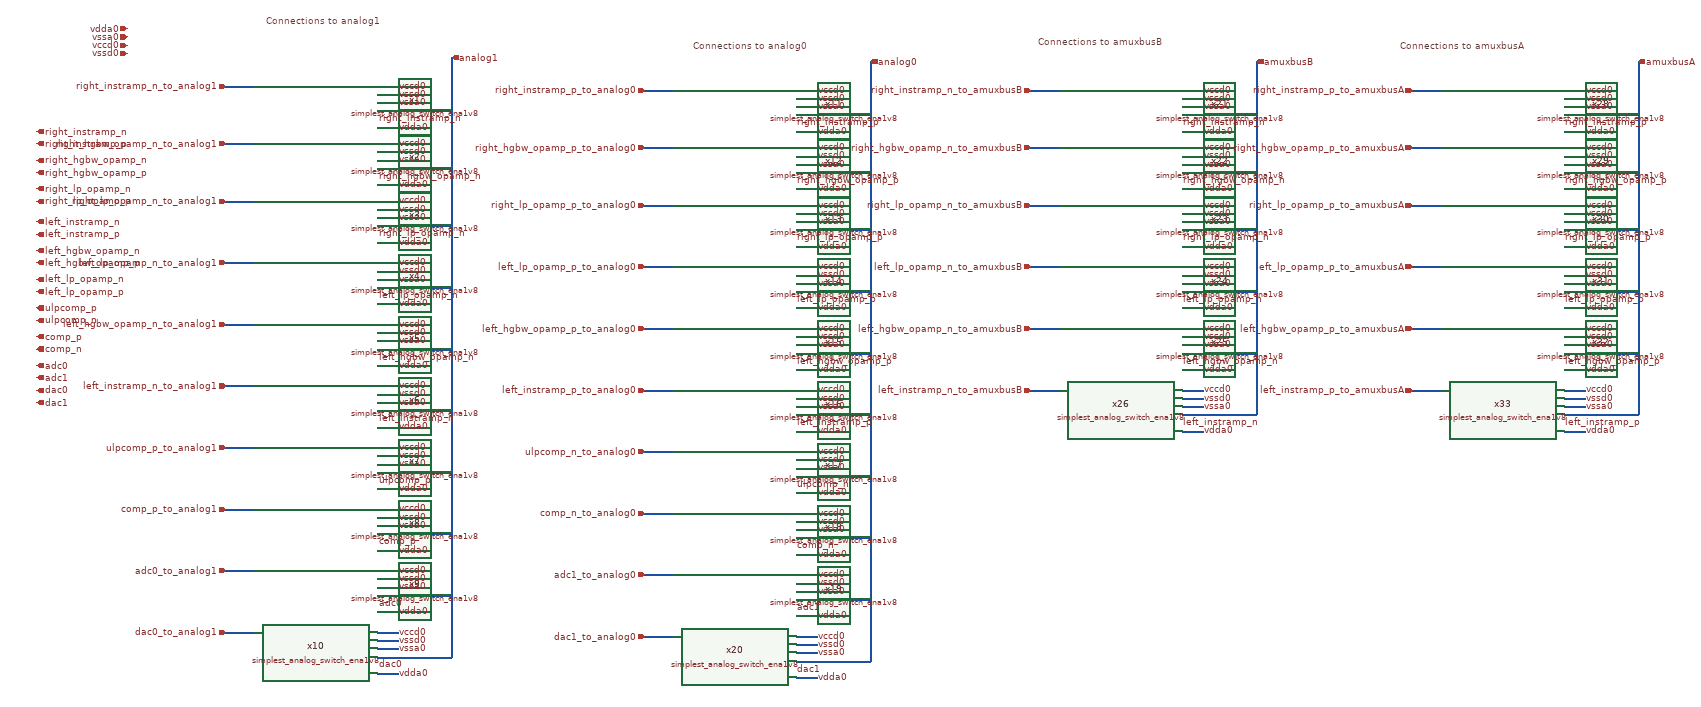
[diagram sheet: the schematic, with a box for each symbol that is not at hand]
v {xschem version=3.4.5 file_version=1.2
}
G {}
K {}
V {}
S {}
E {}
T {Connections to analog1} -110 -190 0 0 0.4 0.4 {}
T {Connections to analog0} 930 -130 0 0 0.4 0.4 {}
T {Connections to amuxbusA} 2650 -130 0 0 0.4 0.4 {}
T {Connections to amuxbusB} 1770 -140 0 0 0.4 0.4 {}
N -210 -20 -140 -20 {
lab=right_instramp_n_to_analog1}
N 160 -20 210 -20 {
lab=vccd0}
N 160 0 210 0 {
lab=vssd0}
N 160 20 210 20 {
lab=vssa0}
N 160 80 210 80 {
lab=vdda0}
N -210 120 -140 120 {
lab=right_hgbw_opamp_n_to_analog1}
N 160 120 210 120 {
lab=vccd0}
N 160 140 210 140 {
lab=vssd0}
N 160 160 210 160 {
lab=vssa0}
N 160 220 210 220 {
lab=vdda0}
N -210 260 -140 260 {
lab=right_lp_opamp_n_to_analog1}
N 160 260 210 260 {
lab=vccd0}
N 160 280 210 280 {
lab=vssd0}
N 160 300 210 300 {
lab=vssa0}
N 160 360 210 360 {
lab=vdda0}
N -210 410 -140 410 {
lab=left_lp_opamp_n_to_analog1}
N 160 410 210 410 {
lab=vccd0}
N 160 430 210 430 {
lab=vssd0}
N 160 450 210 450 {
lab=vssa0}
N 160 510 210 510 {
lab=vdda0}
N 160 40 340 40 {
lab=analog1}
N 160 180 340 180 {
lab=analog1}
N 160 320 340 320 {
lab=analog1}
N 160 470 340 470 {
lab=analog1}
N -210 560 -140 560 {
lab=left_hgbw_opamp_n_to_analog1}
N 160 560 210 560 {
lab=vccd0}
N 160 580 210 580 {
lab=vssd0}
N 160 600 210 600 {
lab=vssa0}
N 160 660 210 660 {
lab=vdda0}
N 160 620 340 620 {
lab=analog1}
N -210 710 -140 710 {
lab=left_instramp_n_to_analog1}
N 160 710 210 710 {
lab=vccd0}
N 160 730 210 730 {
lab=vssd0}
N 160 750 210 750 {
lab=vssa0}
N 160 810 210 810 {
lab=vdda0}
N 160 770 340 770 {
lab=analog1}
N -210 860 -140 860 {
lab=ulpcomp_p_to_analog1}
N 160 860 210 860 {
lab=vccd0}
N 160 880 210 880 {
lab=vssd0}
N 160 900 210 900 {
lab=vssa0}
N 160 960 210 960 {
lab=vdda0}
N 160 920 340 920 {
lab=analog1}
N -210 1010 -140 1010 {
lab=comp_p_to_analog1}
N 160 1010 210 1010 {
lab=vccd0}
N 160 1030 210 1030 {
lab=vssd0}
N 160 1050 210 1050 {
lab=vssa0}
N 160 1110 210 1110 {
lab=vdda0}
N 160 1070 340 1070 {
lab=analog1}
N -210 1160 -140 1160 {
lab=adc0_to_analog1}
N 160 1160 210 1160 {
lab=vccd0}
N 160 1180 210 1180 {
lab=vssd0}
N 160 1200 210 1200 {
lab=vssa0}
N 160 1260 210 1260 {
lab=vdda0}
N 160 1220 340 1220 {
lab=analog1}
N -210 1310 -140 1310 {
lab=dac0_to_analog1}
N 160 1310 210 1310 {
lab=vccd0}
N 160 1330 210 1330 {
lab=vssd0}
N 160 1350 210 1350 {
lab=vssa0}
N 160 1410 210 1410 {
lab=vdda0}
N 160 1370 340 1370 {
lab=analog1}
N 340 -90 340 1370 {
lab=analog1}
N 810 -10 880 -10 {
lab=right_instramp_p_to_analog0}
N 1180 -10 1230 -10 {
lab=vccd0}
N 1180 10 1230 10 {
lab=vssd0}
N 1180 30 1230 30 {
lab=vssa0}
N 1180 90 1230 90 {
lab=vdda0}
N 810 130 880 130 {
lab=right_hgbw_opamp_p_to_analog0}
N 1180 130 1230 130 {
lab=vccd0}
N 1180 150 1230 150 {
lab=vssd0}
N 1180 170 1230 170 {
lab=vssa0}
N 1180 230 1230 230 {
lab=vdda0}
N 810 270 880 270 {
lab=right_lp_opamp_p_to_analog0}
N 1180 270 1230 270 {
lab=vccd0}
N 1180 290 1230 290 {
lab=vssd0}
N 1180 310 1230 310 {
lab=vssa0}
N 1180 370 1230 370 {
lab=vdda0}
N 810 420 880 420 {
lab=left_lp_opamp_p_to_analog0}
N 1180 420 1230 420 {
lab=vccd0}
N 1180 440 1230 440 {
lab=vssd0}
N 1180 460 1230 460 {
lab=vssa0}
N 1180 520 1230 520 {
lab=vdda0}
N 1180 50 1360 50 {
lab=analog0}
N 1180 190 1360 190 {
lab=analog0}
N 1180 330 1360 330 {
lab=analog0}
N 1180 480 1360 480 {
lab=analog0}
N 810 570 880 570 {
lab=left_hgbw_opamp_p_to_analog0}
N 1180 570 1230 570 {
lab=vccd0}
N 1180 590 1230 590 {
lab=vssd0}
N 1180 610 1230 610 {
lab=vssa0}
N 1180 670 1230 670 {
lab=vdda0}
N 1180 630 1360 630 {
lab=analog0}
N 810 720 880 720 {
lab=left_instramp_p_to_analog0}
N 1180 720 1230 720 {
lab=vccd0}
N 1180 740 1230 740 {
lab=vssd0}
N 1180 760 1230 760 {
lab=vssa0}
N 1180 820 1230 820 {
lab=vdda0}
N 1180 780 1360 780 {
lab=analog0}
N 810 870 880 870 {
lab=ulpcomp_n_to_analog0}
N 1180 870 1230 870 {
lab=vccd0}
N 1180 890 1230 890 {
lab=vssd0}
N 1180 910 1230 910 {
lab=vssa0}
N 1180 970 1230 970 {
lab=vdda0}
N 1180 930 1360 930 {
lab=analog0}
N 810 1020 880 1020 {
lab=comp_n_to_analog0}
N 1180 1020 1230 1020 {
lab=vccd0}
N 1180 1040 1230 1040 {
lab=vssd0}
N 1180 1060 1230 1060 {
lab=vssa0}
N 1180 1120 1230 1120 {
lab=vdda0}
N 1180 1080 1360 1080 {
lab=analog0}
N 810 1170 880 1170 {
lab=adc1_to_analog0}
N 1180 1170 1230 1170 {
lab=vccd0}
N 1180 1190 1230 1190 {
lab=vssd0}
N 1180 1210 1230 1210 {
lab=vssa0}
N 1180 1270 1230 1270 {
lab=vdda0}
N 1180 1230 1360 1230 {
lab=analog0}
N 810 1320 880 1320 {
lab=dac1_to_analog0}
N 1180 1320 1230 1320 {
lab=vccd0}
N 1180 1340 1230 1340 {
lab=vssd0}
N 1180 1360 1230 1360 {
lab=vssa0}
N 1180 1420 1230 1420 {
lab=vdda0}
N 1180 1380 1360 1380 {
lab=analog0}
N 1360 -80 1360 1380 {
lab=analog0}
N 1750 -10 1820 -10 {
lab=right_instramp_n_to_amuxbusA}
N 2120 -10 2170 -10 {
lab=vccd0}
N 2120 10 2170 10 {
lab=vssd0}
N 2120 30 2170 30 {
lab=vssa0}
N 2120 90 2170 90 {
lab=vdda0}
N 1750 130 1820 130 {
lab=right_hgbw_opamp_n_to_amuxbusA}
N 2120 130 2170 130 {
lab=vccd0}
N 2120 150 2170 150 {
lab=vssd0}
N 2120 170 2170 170 {
lab=vssa0}
N 2120 230 2170 230 {
lab=vdda0}
N 1750 270 1820 270 {
lab=right_lp_opamp_n_to_amuxbusA}
N 2120 270 2170 270 {
lab=vccd0}
N 2120 290 2170 290 {
lab=vssd0}
N 2120 310 2170 310 {
lab=vssa0}
N 2120 370 2170 370 {
lab=vdda0}
N 1750 420 1820 420 {
lab=left_lp_opamp_n_to_amuxbusA}
N 2120 420 2170 420 {
lab=vccd0}
N 2120 440 2170 440 {
lab=vssd0}
N 2120 460 2170 460 {
lab=vssa0}
N 2120 520 2170 520 {
lab=vdda0}
N 2120 50 2300 50 {
lab=amuxbusA}
N 2120 190 2300 190 {
lab=amuxbusA}
N 2120 330 2300 330 {
lab=amuxbusA}
N 2120 480 2300 480 {
lab=amuxbusA}
N 1750 570 1820 570 {
lab=left_hgbw_opamp_n_to_amuxbusA}
N 2120 570 2170 570 {
lab=vccd0}
N 2120 590 2170 590 {
lab=vssd0}
N 2120 610 2170 610 {
lab=vssa0}
N 2120 670 2170 670 {
lab=vdda0}
N 2120 630 2300 630 {
lab=amuxbusA}
N 1750 720 1820 720 {
lab=left_instramp_n_to_amuxbusA}
N 2120 720 2170 720 {
lab=vccd0}
N 2120 740 2170 740 {
lab=vssd0}
N 2120 760 2170 760 {
lab=vssa0}
N 2120 820 2170 820 {
lab=vdda0}
N 2120 780 2300 780 {
lab=amuxbusA}
N 2680 -10 2750 -10 {
lab=right_instramp_p_to_amuxbusB}
N 3050 -10 3100 -10 {
lab=vccd0}
N 3050 10 3100 10 {
lab=vssd0}
N 3050 30 3100 30 {
lab=vssa0}
N 3050 90 3100 90 {
lab=vdda0}
N 2680 130 2750 130 {
lab=right_hgbw_opamp_p_to_amuxbusB}
N 3050 130 3100 130 {
lab=vccd0}
N 3050 150 3100 150 {
lab=vssd0}
N 3050 170 3100 170 {
lab=vssa0}
N 3050 230 3100 230 {
lab=vdda0}
N 2680 270 2750 270 {
lab=right_lp_opamp_p_to_amuxbusB}
N 3050 270 3100 270 {
lab=vccd0}
N 3050 290 3100 290 {
lab=vssd0}
N 3050 310 3100 310 {
lab=vssa0}
N 3050 370 3100 370 {
lab=vdda0}
N 2680 420 2750 420 {
lab=left_lp_opamp_p_to_amuxbusB}
N 3050 420 3100 420 {
lab=vccd0}
N 3050 440 3100 440 {
lab=vssd0}
N 3050 460 3100 460 {
lab=vssa0}
N 3050 520 3100 520 {
lab=vdda0}
N 3050 50 3230 50 {
lab=amuxbusB}
N 3050 190 3230 190 {
lab=amuxbusB}
N 3050 330 3230 330 {
lab=amuxbusB}
N 3050 480 3230 480 {
lab=amuxbusB}
N 2680 570 2750 570 {
lab=left_hgbw_opamp_p_to_amuxbusB}
N 3050 570 3100 570 {
lab=vccd0}
N 3050 590 3100 590 {
lab=vssd0}
N 3050 610 3100 610 {
lab=vssa0}
N 3050 670 3100 670 {
lab=vdda0}
N 3050 630 3230 630 {
lab=amuxbusB}
N 2680 720 2750 720 {
lab=left_instramp_p_to_amuxbusB}
N 3050 720 3100 720 {
lab=vccd0}
N 3050 740 3100 740 {
lab=vssd0}
N 3050 760 3100 760 {
lab=vssa0}
N 3050 820 3100 820 {
lab=vdda0}
N 3050 780 3230 780 {
lab=amuxbusB}
N 2300 -80 2300 780 {
lab=amuxbusA}
N 3230 -80 3230 780 {
lab=amuxbusB}
C {simplest_analog_switch_ena1v8.sym} 10 30 0 0 {name=x1}
C {devices/iopin.sym} -450 -120 0 0 {name=p1 lab=vccd0}
C {devices/ipin.sym} -210 -20 0 0 {name=p2 lab=right_instramp_n_to_analog1}
C {devices/iopin.sym} -450 -160 0 0 {name=p3 lab=vdda0}
C {devices/iopin.sym} -450 -140 0 0 {name=p4 lab=vssa0}
C {devices/iopin.sym} -450 -100 0 0 {name=p5 lab=vssd0}
C {devices/lab_pin.sym} 210 -20 0 1 {name=p6 sig_type=std_logic lab=vccd0}
C {devices/lab_pin.sym} 210 0 0 1 {name=p7 sig_type=std_logic lab=vssd0}
C {devices/lab_pin.sym} 210 20 0 1 {name=p8 sig_type=std_logic lab=vssa0}
C {devices/lab_pin.sym} 210 80 0 1 {name=p9 sig_type=std_logic lab=vdda0}
C {simplest_analog_switch_ena1v8.sym} 10 170 0 0 {name=x2}
C {devices/ipin.sym} -210 120 0 0 {name=p10 lab=right_hgbw_opamp_n_to_analog1}
C {devices/lab_pin.sym} 210 120 0 1 {name=p11 sig_type=std_logic lab=vccd0}
C {devices/lab_pin.sym} 210 140 0 1 {name=p12 sig_type=std_logic lab=vssd0}
C {devices/lab_pin.sym} 210 160 0 1 {name=p13 sig_type=std_logic lab=vssa0}
C {devices/lab_pin.sym} 210 220 0 1 {name=p14 sig_type=std_logic lab=vdda0}
C {simplest_analog_switch_ena1v8.sym} 10 310 0 0 {name=x3}
C {devices/ipin.sym} -210 260 0 0 {name=p15 lab=right_lp_opamp_n_to_analog1}
C {devices/lab_pin.sym} 210 260 0 1 {name=p16 sig_type=std_logic lab=vccd0}
C {devices/lab_pin.sym} 210 280 0 1 {name=p17 sig_type=std_logic lab=vssd0}
C {devices/lab_pin.sym} 210 300 0 1 {name=p18 sig_type=std_logic lab=vssa0}
C {devices/lab_pin.sym} 210 360 0 1 {name=p19 sig_type=std_logic lab=vdda0}
C {simplest_analog_switch_ena1v8.sym} 10 460 0 0 {name=x4}
C {devices/ipin.sym} -210 410 0 0 {name=p20 lab=left_lp_opamp_n_to_analog1}
C {devices/lab_pin.sym} 210 410 0 1 {name=p21 sig_type=std_logic lab=vccd0}
C {devices/lab_pin.sym} 210 430 0 1 {name=p22 sig_type=std_logic lab=vssd0}
C {devices/lab_pin.sym} 210 450 0 1 {name=p23 sig_type=std_logic lab=vssa0}
C {devices/lab_pin.sym} 210 510 0 1 {name=p24 sig_type=std_logic lab=vdda0}
C {simplest_analog_switch_ena1v8.sym} 10 610 0 0 {name=x5}
C {devices/ipin.sym} -210 560 0 0 {name=p25 lab=left_hgbw_opamp_n_to_analog1}
C {devices/lab_pin.sym} 210 560 0 1 {name=p26 sig_type=std_logic lab=vccd0}
C {devices/lab_pin.sym} 210 580 0 1 {name=p27 sig_type=std_logic lab=vssd0}
C {devices/lab_pin.sym} 210 600 0 1 {name=p28 sig_type=std_logic lab=vssa0}
C {devices/lab_pin.sym} 210 660 0 1 {name=p29 sig_type=std_logic lab=vdda0}
C {simplest_analog_switch_ena1v8.sym} 10 760 0 0 {name=x6}
C {devices/ipin.sym} -210 710 0 0 {name=p30 lab=left_instramp_n_to_analog1}
C {devices/lab_pin.sym} 210 710 0 1 {name=p31 sig_type=std_logic lab=vccd0}
C {devices/lab_pin.sym} 210 730 0 1 {name=p32 sig_type=std_logic lab=vssd0}
C {devices/lab_pin.sym} 210 750 0 1 {name=p33 sig_type=std_logic lab=vssa0}
C {devices/lab_pin.sym} 210 810 0 1 {name=p34 sig_type=std_logic lab=vdda0}
C {simplest_analog_switch_ena1v8.sym} 10 910 0 0 {name=x7}
C {devices/ipin.sym} -210 860 0 0 {name=p35 lab=ulpcomp_p_to_analog1}
C {devices/lab_pin.sym} 210 860 0 1 {name=p36 sig_type=std_logic lab=vccd0}
C {devices/lab_pin.sym} 210 880 0 1 {name=p37 sig_type=std_logic lab=vssd0}
C {devices/lab_pin.sym} 210 900 0 1 {name=p38 sig_type=std_logic lab=vssa0}
C {devices/lab_pin.sym} 210 960 0 1 {name=p39 sig_type=std_logic lab=vdda0}
C {simplest_analog_switch_ena1v8.sym} 10 1060 0 0 {name=x8}
C {devices/ipin.sym} -210 1010 0 0 {name=p40 lab=comp_p_to_analog1}
C {devices/lab_pin.sym} 210 1010 0 1 {name=p41 sig_type=std_logic lab=vccd0}
C {devices/lab_pin.sym} 210 1030 0 1 {name=p42 sig_type=std_logic lab=vssd0}
C {devices/lab_pin.sym} 210 1050 0 1 {name=p43 sig_type=std_logic lab=vssa0}
C {devices/lab_pin.sym} 210 1110 0 1 {name=p44 sig_type=std_logic lab=vdda0}
C {simplest_analog_switch_ena1v8.sym} 10 1210 0 0 {name=x9}
C {devices/ipin.sym} -210 1160 0 0 {name=p45 lab=adc0_to_analog1}
C {devices/lab_pin.sym} 210 1160 0 1 {name=p46 sig_type=std_logic lab=vccd0}
C {devices/lab_pin.sym} 210 1180 0 1 {name=p47 sig_type=std_logic lab=vssd0}
C {devices/lab_pin.sym} 210 1200 0 1 {name=p48 sig_type=std_logic lab=vssa0}
C {devices/lab_pin.sym} 210 1260 0 1 {name=p49 sig_type=std_logic lab=vdda0}
C {simplest_analog_switch_ena1v8.sym} 10 1360 0 0 {name=x10}
C {devices/ipin.sym} -210 1310 0 0 {name=p50 lab=dac0_to_analog1}
C {devices/lab_pin.sym} 210 1310 0 1 {name=p51 sig_type=std_logic lab=vccd0}
C {devices/lab_pin.sym} 210 1330 0 1 {name=p52 sig_type=std_logic lab=vssd0}
C {devices/lab_pin.sym} 210 1350 0 1 {name=p53 sig_type=std_logic lab=vssa0}
C {devices/lab_pin.sym} 210 1410 0 1 {name=p54 sig_type=std_logic lab=vdda0}
C {devices/iopin.sym} 340 -90 0 1 {name=p55 lab=analog1}
C {simplest_analog_switch_ena1v8.sym} 1030 40 0 0 {name=x11}
C {devices/ipin.sym} 810 -10 0 0 {name=p56 lab=right_instramp_p_to_analog0}
C {devices/lab_pin.sym} 1230 -10 0 1 {name=p57 sig_type=std_logic lab=vccd0}
C {devices/lab_pin.sym} 1230 10 0 1 {name=p58 sig_type=std_logic lab=vssd0}
C {devices/lab_pin.sym} 1230 30 0 1 {name=p59 sig_type=std_logic lab=vssa0}
C {devices/lab_pin.sym} 1230 90 0 1 {name=p60 sig_type=std_logic lab=vdda0}
C {simplest_analog_switch_ena1v8.sym} 1030 180 0 0 {name=x12}
C {devices/ipin.sym} 810 130 0 0 {name=p61 lab=right_hgbw_opamp_p_to_analog0}
C {devices/lab_pin.sym} 1230 130 0 1 {name=p62 sig_type=std_logic lab=vccd0}
C {devices/lab_pin.sym} 1230 150 0 1 {name=p63 sig_type=std_logic lab=vssd0}
C {devices/lab_pin.sym} 1230 170 0 1 {name=p64 sig_type=std_logic lab=vssa0}
C {devices/lab_pin.sym} 1230 230 0 1 {name=p65 sig_type=std_logic lab=vdda0}
C {simplest_analog_switch_ena1v8.sym} 1030 320 0 0 {name=x13}
C {devices/ipin.sym} 810 270 0 0 {name=p66 lab=right_lp_opamp_p_to_analog0}
C {devices/lab_pin.sym} 1230 270 0 1 {name=p67 sig_type=std_logic lab=vccd0}
C {devices/lab_pin.sym} 1230 290 0 1 {name=p68 sig_type=std_logic lab=vssd0}
C {devices/lab_pin.sym} 1230 310 0 1 {name=p69 sig_type=std_logic lab=vssa0}
C {devices/lab_pin.sym} 1230 370 0 1 {name=p70 sig_type=std_logic lab=vdda0}
C {simplest_analog_switch_ena1v8.sym} 1030 470 0 0 {name=x14}
C {devices/ipin.sym} 810 420 0 0 {name=p71 lab=left_lp_opamp_p_to_analog0}
C {devices/lab_pin.sym} 1230 420 0 1 {name=p72 sig_type=std_logic lab=vccd0}
C {devices/lab_pin.sym} 1230 440 0 1 {name=p73 sig_type=std_logic lab=vssd0}
C {devices/lab_pin.sym} 1230 460 0 1 {name=p74 sig_type=std_logic lab=vssa0}
C {devices/lab_pin.sym} 1230 520 0 1 {name=p75 sig_type=std_logic lab=vdda0}
C {simplest_analog_switch_ena1v8.sym} 1030 620 0 0 {name=x15}
C {devices/ipin.sym} 810 570 0 0 {name=p76 lab=left_hgbw_opamp_p_to_analog0}
C {devices/lab_pin.sym} 1230 570 0 1 {name=p77 sig_type=std_logic lab=vccd0}
C {devices/lab_pin.sym} 1230 590 0 1 {name=p78 sig_type=std_logic lab=vssd0}
C {devices/lab_pin.sym} 1230 610 0 1 {name=p79 sig_type=std_logic lab=vssa0}
C {devices/lab_pin.sym} 1230 670 0 1 {name=p80 sig_type=std_logic lab=vdda0}
C {simplest_analog_switch_ena1v8.sym} 1030 770 0 0 {name=x16}
C {devices/ipin.sym} 810 720 0 0 {name=p81 lab=left_instramp_p_to_analog0}
C {devices/lab_pin.sym} 1230 720 0 1 {name=p82 sig_type=std_logic lab=vccd0}
C {devices/lab_pin.sym} 1230 740 0 1 {name=p83 sig_type=std_logic lab=vssd0}
C {devices/lab_pin.sym} 1230 760 0 1 {name=p84 sig_type=std_logic lab=vssa0}
C {devices/lab_pin.sym} 1230 820 0 1 {name=p85 sig_type=std_logic lab=vdda0}
C {simplest_analog_switch_ena1v8.sym} 1030 920 0 0 {name=x17}
C {devices/ipin.sym} 810 870 0 0 {name=p86 lab=ulpcomp_n_to_analog0}
C {devices/lab_pin.sym} 1230 870 0 1 {name=p87 sig_type=std_logic lab=vccd0}
C {devices/lab_pin.sym} 1230 890 0 1 {name=p88 sig_type=std_logic lab=vssd0}
C {devices/lab_pin.sym} 1230 910 0 1 {name=p89 sig_type=std_logic lab=vssa0}
C {devices/lab_pin.sym} 1230 970 0 1 {name=p90 sig_type=std_logic lab=vdda0}
C {simplest_analog_switch_ena1v8.sym} 1030 1070 0 0 {name=x18}
C {devices/ipin.sym} 810 1020 0 0 {name=p91 lab=comp_n_to_analog0}
C {devices/lab_pin.sym} 1230 1020 0 1 {name=p92 sig_type=std_logic lab=vccd0}
C {devices/lab_pin.sym} 1230 1040 0 1 {name=p93 sig_type=std_logic lab=vssd0}
C {devices/lab_pin.sym} 1230 1060 0 1 {name=p94 sig_type=std_logic lab=vssa0}
C {devices/lab_pin.sym} 1230 1120 0 1 {name=p95 sig_type=std_logic lab=vdda0}
C {simplest_analog_switch_ena1v8.sym} 1030 1220 0 0 {name=x19}
C {devices/ipin.sym} 810 1170 0 0 {name=p96 lab=adc1_to_analog0}
C {devices/lab_pin.sym} 1230 1170 0 1 {name=p97 sig_type=std_logic lab=vccd0}
C {devices/lab_pin.sym} 1230 1190 0 1 {name=p98 sig_type=std_logic lab=vssd0}
C {devices/lab_pin.sym} 1230 1210 0 1 {name=p99 sig_type=std_logic lab=vssa0}
C {devices/lab_pin.sym} 1230 1270 0 1 {name=p100 sig_type=std_logic lab=vdda0}
C {simplest_analog_switch_ena1v8.sym} 1030 1370 0 0 {name=x20}
C {devices/ipin.sym} 810 1320 0 0 {name=p101 lab=dac1_to_analog0}
C {devices/lab_pin.sym} 1230 1320 0 1 {name=p102 sig_type=std_logic lab=vccd0}
C {devices/lab_pin.sym} 1230 1340 0 1 {name=p103 sig_type=std_logic lab=vssd0}
C {devices/lab_pin.sym} 1230 1360 0 1 {name=p104 sig_type=std_logic lab=vssa0}
C {devices/lab_pin.sym} 1230 1420 0 1 {name=p105 sig_type=std_logic lab=vdda0}
C {devices/iopin.sym} 1360 -80 0 1 {name=p106 lab=analog0}
C {simplest_analog_switch_ena1v8.sym} 1970 40 0 0 {name=x21}
C {devices/lab_pin.sym} 2170 -10 0 1 {name=p108 sig_type=std_logic lab=vccd0}
C {devices/lab_pin.sym} 2170 10 0 1 {name=p109 sig_type=std_logic lab=vssd0}
C {devices/lab_pin.sym} 2170 30 0 1 {name=p110 sig_type=std_logic lab=vssa0}
C {devices/lab_pin.sym} 2170 90 0 1 {name=p111 sig_type=std_logic lab=vdda0}
C {simplest_analog_switch_ena1v8.sym} 1970 180 0 0 {name=x22}
C {devices/lab_pin.sym} 2170 130 0 1 {name=p113 sig_type=std_logic lab=vccd0}
C {devices/lab_pin.sym} 2170 150 0 1 {name=p114 sig_type=std_logic lab=vssd0}
C {devices/lab_pin.sym} 2170 170 0 1 {name=p115 sig_type=std_logic lab=vssa0}
C {devices/lab_pin.sym} 2170 230 0 1 {name=p116 sig_type=std_logic lab=vdda0}
C {simplest_analog_switch_ena1v8.sym} 1970 320 0 0 {name=x23}
C {devices/lab_pin.sym} 2170 270 0 1 {name=p118 sig_type=std_logic lab=vccd0}
C {devices/lab_pin.sym} 2170 290 0 1 {name=p119 sig_type=std_logic lab=vssd0}
C {devices/lab_pin.sym} 2170 310 0 1 {name=p120 sig_type=std_logic lab=vssa0}
C {devices/lab_pin.sym} 2170 370 0 1 {name=p121 sig_type=std_logic lab=vdda0}
C {simplest_analog_switch_ena1v8.sym} 1970 470 0 0 {name=x24}
C {devices/lab_pin.sym} 2170 420 0 1 {name=p123 sig_type=std_logic lab=vccd0}
C {devices/lab_pin.sym} 2170 440 0 1 {name=p124 sig_type=std_logic lab=vssd0}
C {devices/lab_pin.sym} 2170 460 0 1 {name=p125 sig_type=std_logic lab=vssa0}
C {devices/lab_pin.sym} 2170 520 0 1 {name=p126 sig_type=std_logic lab=vdda0}
C {simplest_analog_switch_ena1v8.sym} 1970 620 0 0 {name=x25}
C {devices/lab_pin.sym} 2170 570 0 1 {name=p128 sig_type=std_logic lab=vccd0}
C {devices/lab_pin.sym} 2170 590 0 1 {name=p129 sig_type=std_logic lab=vssd0}
C {devices/lab_pin.sym} 2170 610 0 1 {name=p130 sig_type=std_logic lab=vssa0}
C {devices/lab_pin.sym} 2170 670 0 1 {name=p131 sig_type=std_logic lab=vdda0}
C {simplest_analog_switch_ena1v8.sym} 1970 770 0 0 {name=x26}
C {devices/lab_pin.sym} 2170 720 0 1 {name=p133 sig_type=std_logic lab=vccd0}
C {devices/lab_pin.sym} 2170 740 0 1 {name=p134 sig_type=std_logic lab=vssd0}
C {devices/lab_pin.sym} 2170 760 0 1 {name=p135 sig_type=std_logic lab=vssa0}
C {devices/lab_pin.sym} 2170 820 0 1 {name=p136 sig_type=std_logic lab=vdda0}
C {devices/iopin.sym} 3230 -80 0 1 {name=p142 lab=amuxbusA}
C {simplest_analog_switch_ena1v8.sym} 2900 40 0 0 {name=x28}
C {devices/ipin.sym} 2680 -10 0 0 {name=p143 lab=right_instramp_p_to_amuxbusA}
C {devices/lab_pin.sym} 3100 -10 0 1 {name=p144 sig_type=std_logic lab=vccd0}
C {devices/lab_pin.sym} 3100 10 0 1 {name=p145 sig_type=std_logic lab=vssd0}
C {devices/lab_pin.sym} 3100 30 0 1 {name=p146 sig_type=std_logic lab=vssa0}
C {devices/lab_pin.sym} 3100 90 0 1 {name=p147 sig_type=std_logic lab=vdda0}
C {simplest_analog_switch_ena1v8.sym} 2900 180 0 0 {name=x29}
C {devices/ipin.sym} 2680 130 0 0 {name=p148 lab=right_hgbw_opamp_p_to_amuxbusA}
C {devices/lab_pin.sym} 3100 130 0 1 {name=p149 sig_type=std_logic lab=vccd0}
C {devices/lab_pin.sym} 3100 150 0 1 {name=p150 sig_type=std_logic lab=vssd0}
C {devices/lab_pin.sym} 3100 170 0 1 {name=p151 sig_type=std_logic lab=vssa0}
C {devices/lab_pin.sym} 3100 230 0 1 {name=p152 sig_type=std_logic lab=vdda0}
C {simplest_analog_switch_ena1v8.sym} 2900 320 0 0 {name=x30}
C {devices/ipin.sym} 2680 270 0 0 {name=p153 lab=right_lp_opamp_p_to_amuxbusA}
C {devices/lab_pin.sym} 3100 270 0 1 {name=p154 sig_type=std_logic lab=vccd0}
C {devices/lab_pin.sym} 3100 290 0 1 {name=p155 sig_type=std_logic lab=vssd0}
C {devices/lab_pin.sym} 3100 310 0 1 {name=p156 sig_type=std_logic lab=vssa0}
C {devices/lab_pin.sym} 3100 370 0 1 {name=p157 sig_type=std_logic lab=vdda0}
C {simplest_analog_switch_ena1v8.sym} 2900 470 0 0 {name=x31}
C {devices/ipin.sym} 2680 420 0 0 {name=p158 lab=left_lp_opamp_p_to_amuxbusA}
C {devices/lab_pin.sym} 3100 420 0 1 {name=p159 sig_type=std_logic lab=vccd0}
C {devices/lab_pin.sym} 3100 440 0 1 {name=p160 sig_type=std_logic lab=vssd0}
C {devices/lab_pin.sym} 3100 460 0 1 {name=p161 sig_type=std_logic lab=vssa0}
C {devices/lab_pin.sym} 3100 520 0 1 {name=p162 sig_type=std_logic lab=vdda0}
C {simplest_analog_switch_ena1v8.sym} 2900 620 0 0 {name=x32}
C {devices/ipin.sym} 2680 570 0 0 {name=p163 lab=left_hgbw_opamp_p_to_amuxbusA}
C {devices/lab_pin.sym} 3100 570 0 1 {name=p164 sig_type=std_logic lab=vccd0}
C {devices/lab_pin.sym} 3100 590 0 1 {name=p165 sig_type=std_logic lab=vssd0}
C {devices/lab_pin.sym} 3100 610 0 1 {name=p166 sig_type=std_logic lab=vssa0}
C {devices/lab_pin.sym} 3100 670 0 1 {name=p167 sig_type=std_logic lab=vdda0}
C {simplest_analog_switch_ena1v8.sym} 2900 770 0 0 {name=x33}
C {devices/ipin.sym} 2680 720 0 0 {name=p168 lab=left_instramp_p_to_amuxbusA}
C {devices/lab_pin.sym} 3100 720 0 1 {name=p169 sig_type=std_logic lab=vccd0}
C {devices/lab_pin.sym} 3100 740 0 1 {name=p170 sig_type=std_logic lab=vssd0}
C {devices/lab_pin.sym} 3100 760 0 1 {name=p171 sig_type=std_logic lab=vssa0}
C {devices/lab_pin.sym} 3100 820 0 1 {name=p172 sig_type=std_logic lab=vdda0}
C {devices/iopin.sym} 2300 -80 0 1 {name=p178 lab=amuxbusB}
C {devices/ipin.sym} 1750 -10 0 0 {name=p107 lab=right_instramp_n_to_amuxbusB}
C {devices/ipin.sym} 1750 130 0 0 {name=p112 lab=right_hgbw_opamp_n_to_amuxbusB}
C {devices/ipin.sym} 1750 270 0 0 {name=p117 lab=right_lp_opamp_n_to_amuxbusB}
C {devices/ipin.sym} 1750 420 0 0 {name=p122 lab=left_lp_opamp_n_to_amuxbusB}
C {devices/ipin.sym} 1750 570 0 0 {name=p127 lab=left_hgbw_opamp_n_to_amuxbusB}
C {devices/ipin.sym} 1750 720 0 0 {name=p132 lab=left_instramp_n_to_amuxbusB}
C {devices/iopin.sym} -670 90 0 1 {name=p137 lab=right_instramp_n}
C {devices/iopin.sym} -670 120 0 1 {name=p138 lab=right_instramp_p}
C {devices/iopin.sym} -670 160 0 1 {name=p139 lab=right_hgbw_opamp_n}
C {devices/iopin.sym} -670 190 0 1 {name=p140 lab=right_hgbw_opamp_p}
C {devices/iopin.sym} -670 230 0 1 {name=p141 lab=right_lp_opamp_n}
C {devices/iopin.sym} -670 260 0 1 {name=p173 lab=right_lp_opamp_p}
C {devices/iopin.sym} -670 310 0 1 {name=p174 lab=left_instramp_n}
C {devices/iopin.sym} -670 340 0 1 {name=p175 lab=left_instramp_p}
C {devices/iopin.sym} -670 380 0 1 {name=p176 lab=left_hgbw_opamp_n}
C {devices/iopin.sym} -670 410 0 1 {name=p177 lab=left_hgbw_opamp_p}
C {devices/iopin.sym} -670 450 0 1 {name=p179 lab=left_lp_opamp_n}
C {devices/iopin.sym} -670 480 0 1 {name=p180 lab=left_lp_opamp_p}
C {devices/iopin.sym} -670 520 0 1 {name=p181 lab=ulpcomp_p}
C {devices/iopin.sym} -670 550 0 1 {name=p182 lab=ulpcomp_n}
C {devices/iopin.sym} -670 590 0 1 {name=p183 lab=comp_p}
C {devices/iopin.sym} -670 620 0 1 {name=p184 lab=comp_n}
C {devices/iopin.sym} -670 660 0 1 {name=p185 lab=adc0}
C {devices/iopin.sym} -670 690 0 1 {name=p186 lab=adc1}
C {devices/iopin.sym} -670 720 0 1 {name=p187 lab=dac0}
C {devices/iopin.sym} -670 750 0 1 {name=p188 lab=dac1}
C {devices/lab_pin.sym} 160 60 0 1 {name=p189 sig_type=std_logic lab=right_instramp_n}
C {devices/lab_pin.sym} 160 200 0 1 {name=p190 sig_type=std_logic lab=right_hgbw_opamp_n}
C {devices/lab_pin.sym} 160 340 0 1 {name=p191 sig_type=std_logic lab=right_lp_opamp_n}
C {devices/lab_pin.sym} 160 490 0 1 {name=p192 sig_type=std_logic lab=left_lp_opamp_n}
C {devices/lab_pin.sym} 160 640 0 1 {name=p193 sig_type=std_logic lab=left_hgbw_opamp_n}
C {devices/lab_pin.sym} 160 790 0 1 {name=p194 sig_type=std_logic lab=left_instramp_n}
C {devices/lab_pin.sym} 160 940 0 1 {name=p195 sig_type=std_logic lab=ulpcomp_p}
C {devices/lab_pin.sym} 160 1090 0 1 {name=p196 sig_type=std_logic lab=comp_p}
C {devices/lab_pin.sym} 160 1240 0 1 {name=p197 sig_type=std_logic lab=adc0}
C {devices/lab_pin.sym} 160 1390 0 1 {name=p198 sig_type=std_logic lab=dac0}
C {devices/lab_pin.sym} 1180 1400 0 1 {name=p199 sig_type=std_logic lab=dac1}
C {devices/lab_pin.sym} 1180 1250 0 1 {name=p200 sig_type=std_logic lab=adc1}
C {devices/lab_pin.sym} 1180 650 0 1 {name=p201 sig_type=std_logic lab=left_hgbw_opamp_p}
C {devices/lab_pin.sym} 1180 800 0 1 {name=p202 sig_type=std_logic lab=left_instramp_p}
C {devices/lab_pin.sym} 1180 950 0 1 {name=p203 sig_type=std_logic lab=ulpcomp_n}
C {devices/lab_pin.sym} 1180 1100 0 1 {name=p204 sig_type=std_logic lab=comp_n}
C {devices/lab_pin.sym} 1180 70 0 1 {name=p205 sig_type=std_logic lab=right_instramp_p}
C {devices/lab_pin.sym} 1180 210 0 1 {name=p206 sig_type=std_logic lab=right_hgbw_opamp_p}
C {devices/lab_pin.sym} 1180 350 0 1 {name=p207 sig_type=std_logic lab=right_lp_opamp_p}
C {devices/lab_pin.sym} 1180 500 0 1 {name=p208 sig_type=std_logic lab=left_lp_opamp_p}
C {devices/lab_pin.sym} 2120 70 0 1 {name=p209 sig_type=std_logic lab=right_instramp_n}
C {devices/lab_pin.sym} 2120 210 0 1 {name=p210 sig_type=std_logic lab=right_hgbw_opamp_n}
C {devices/lab_pin.sym} 2120 350 0 1 {name=p211 sig_type=std_logic lab=right_lp_opamp_n}
C {devices/lab_pin.sym} 2120 500 0 1 {name=p212 sig_type=std_logic lab=left_lp_opamp_n}
C {devices/lab_pin.sym} 2120 650 0 1 {name=p213 sig_type=std_logic lab=left_hgbw_opamp_n}
C {devices/lab_pin.sym} 2120 800 0 1 {name=p214 sig_type=std_logic lab=left_instramp_n}
C {devices/lab_pin.sym} 3050 650 0 1 {name=p215 sig_type=std_logic lab=left_hgbw_opamp_p}
C {devices/lab_pin.sym} 3050 800 0 1 {name=p216 sig_type=std_logic lab=left_instramp_p}
C {devices/lab_pin.sym} 3050 70 0 1 {name=p217 sig_type=std_logic lab=right_instramp_p}
C {devices/lab_pin.sym} 3050 210 0 1 {name=p218 sig_type=std_logic lab=right_hgbw_opamp_p}
C {devices/lab_pin.sym} 3050 350 0 1 {name=p219 sig_type=std_logic lab=right_lp_opamp_p}
C {devices/lab_pin.sym} 3050 500 0 1 {name=p220 sig_type=std_logic lab=left_lp_opamp_p}
